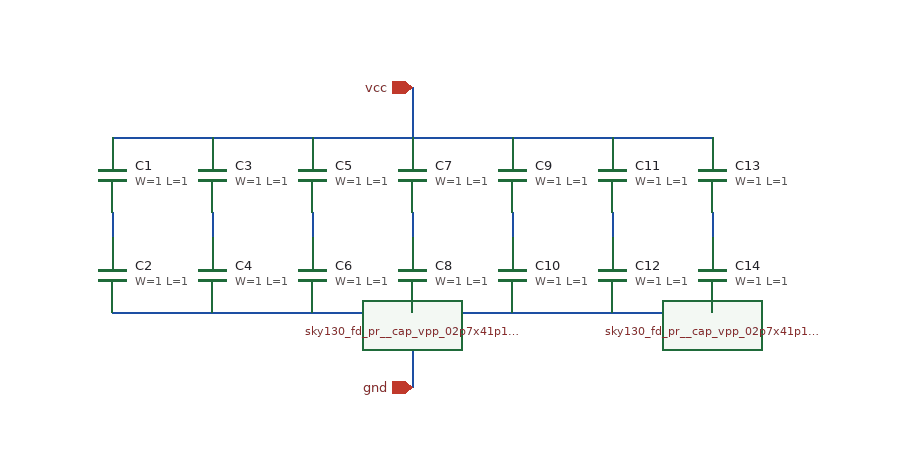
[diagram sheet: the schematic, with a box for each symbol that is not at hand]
v {xschem version=3.0.0 file_version=1.2 }
G {}
K {}
V {}
S {}
E {}
N 180 -340 660 -340 {
lab=vcc}
N 180 -200 660 -200 {
lab=#net1}
N 660 -280 660 -260 {
lab=#net2}
N 580 -280 580 -260 {
lab=#net3}
N 500 -280 500 -260 {
lab=#net4}
N 420 -280 420 -260 {
lab=#net5}
N 340 -280 340 -260 {
lab=#net6}
N 260 -280 260 -260 {
lab=#net7}
N 180 -280 180 -260 {
lab=#net8}
N 420 -200 420 -140 {
lab=#net1}
N 420 -380 420 -340 {
lab=vcc}
C {/foss/pdk/sky130A/libs.ref/sky130_fd_pr/spice/sky130_fd_pr__cap_vpp_02p7x41p1_m1m2m3m4_shieldl1_fingercap.spice} 420 -190 0 0 {}
C {/foss/pdk/sky130A/libs.tech/xschem/sky130_fd_pr/cap_mim_m3_1.sym} 180 -310 0 0 {name=C1 model=cap_mim_m3_1 W=1 L=1 MF=1 spiceprefix=X}
C {/foss/pdk/sky130A/libs.tech/xschem/sky130_fd_pr/cap_mim_m3_1.sym} 180 -230 0 0 {name=C2 model=cap_mim_m3_1 W=1 L=1 MF=1 spiceprefix=X}
C {/foss/pdk/sky130A/libs.tech/xschem/sky130_fd_pr/cap_mim_m3_1.sym} 260 -310 0 0 {name=C3 model=cap_mim_m3_1 W=1 L=1 MF=1 spiceprefix=X}
C {/foss/pdk/sky130A/libs.tech/xschem/sky130_fd_pr/cap_mim_m3_1.sym} 260 -230 0 0 {name=C4 model=cap_mim_m3_1 W=1 L=1 MF=1 spiceprefix=X}
C {/foss/pdk/sky130A/libs.tech/xschem/sky130_fd_pr/cap_mim_m3_1.sym} 340 -310 0 0 {name=C5 model=cap_mim_m3_1 W=1 L=1 MF=1 spiceprefix=X}
C {/foss/pdk/sky130A/libs.tech/xschem/sky130_fd_pr/cap_mim_m3_1.sym} 340 -230 0 0 {name=C6 model=cap_mim_m3_1 W=1 L=1 MF=1 spiceprefix=X}
C {/foss/pdk/sky130A/libs.tech/xschem/sky130_fd_pr/cap_mim_m3_1.sym} 420 -310 0 0 {name=C7 model=cap_mim_m3_1 W=1 L=1 MF=1 spiceprefix=X}
C {/foss/pdk/sky130A/libs.tech/xschem/sky130_fd_pr/cap_mim_m3_1.sym} 420 -230 0 0 {name=C8 model=cap_mim_m3_1 W=1 L=1 MF=1 spiceprefix=X}
C {/foss/pdk/sky130A/libs.ref/sky130_fd_pr/spice/sky130_fd_pr__cap_vpp_02p7x41p1_m1m2m3m4_shieldl1_fingercap.spice} 660 -190 0 0 {}
C {/foss/pdk/sky130A/libs.tech/xschem/sky130_fd_pr/cap_mim_m3_1.sym} 500 -310 0 0 {name=C9 model=cap_mim_m3_1 W=1 L=1 MF=1 spiceprefix=X}
C {/foss/pdk/sky130A/libs.tech/xschem/sky130_fd_pr/cap_mim_m3_1.sym} 500 -230 0 0 {name=C10 model=cap_mim_m3_1 W=1 L=1 MF=1 spiceprefix=X}
C {/foss/pdk/sky130A/libs.tech/xschem/sky130_fd_pr/cap_mim_m3_1.sym} 580 -310 0 0 {name=C11 model=cap_mim_m3_1 W=1 L=1 MF=1 spiceprefix=X}
C {/foss/pdk/sky130A/libs.tech/xschem/sky130_fd_pr/cap_mim_m3_1.sym} 580 -230 0 0 {name=C12 model=cap_mim_m3_1 W=1 L=1 MF=1 spiceprefix=X}
C {/foss/pdk/sky130A/libs.tech/xschem/sky130_fd_pr/cap_mim_m3_1.sym} 660 -310 0 0 {name=C13 model=cap_mim_m3_1 W=1 L=1 MF=1 spiceprefix=X}
C {/foss/pdk/sky130A/libs.tech/xschem/sky130_fd_pr/cap_mim_m3_1.sym} 660 -230 0 0 {name=C14 model=cap_mim_m3_1 W=1 L=1 MF=1 spiceprefix=X}
C {ipin.sym} 420 -380 1 0 {name=vcc lab=vcc}
C {ipin.sym} 420 -140 3 0 {name=gnd lab=gnd}
